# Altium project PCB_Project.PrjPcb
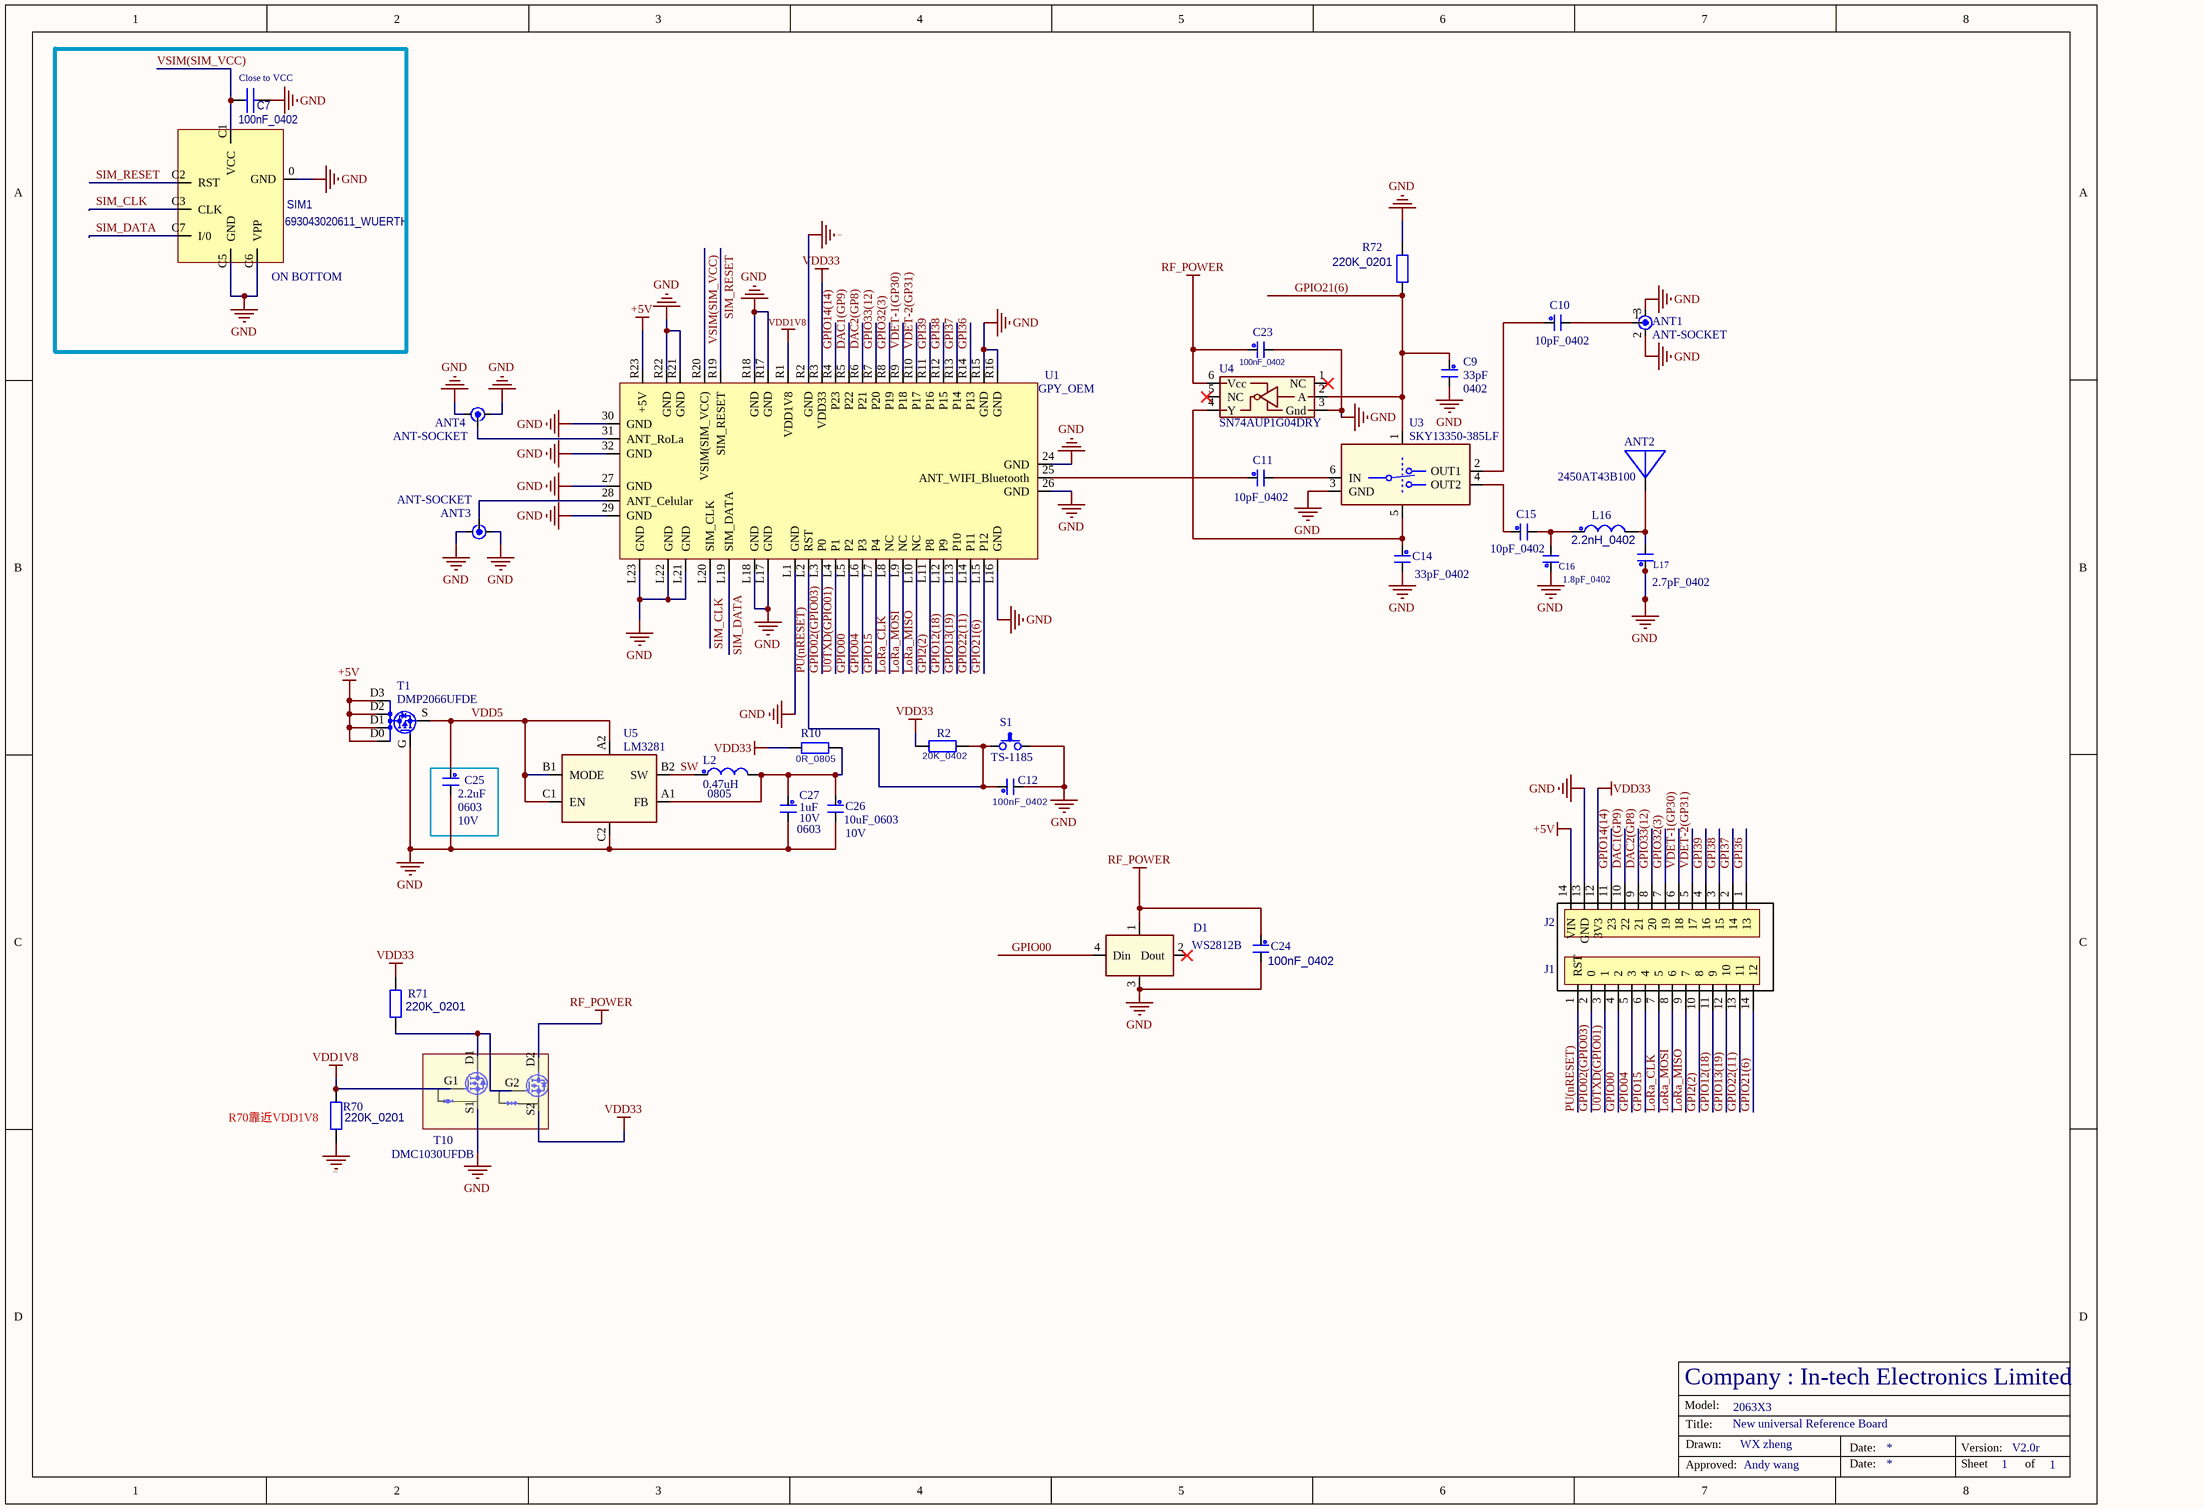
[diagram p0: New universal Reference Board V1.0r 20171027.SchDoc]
1 sheet, 36 parts. Net scope: global (net labels, ports and power ports of the same name join across sheets).
Board file: New universal Reference Board V1.0r 20171201.PcbDoc

## Sheet New universal Reference Board V1.0r 20171027.SchDoc: G01 Reference Board V1.0r
size A3; ApprovedBy: Andy wang; DrawnBy: WX zheng; Address1: 2063X3; Address2: New universal Reference Board; Address3: V2.0r; Address4: C; DocumentNumber: 1; SheetNumber: 1; SheetTotal: 1

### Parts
ANT1  ANT-SOCKET  [ANT-SOCKET]
ANT2  value 2450AT43B100  [ANT-2450AT43B100]  (hidden comment: ANT2450AT43B100)
ANT3  ANT-SOCKET  [ANT-SOCKET]
ANT4  ANT-SOCKET  [ANT-SOCKET]
C7  100nF_0402  [0402C]
C9  value 33pF  PCB DECAL: 0402  [0402C]  (hidden comment: 33pF_0402)
C10  10pF_0402  [0402C]
C11  10pF_0402  [0402C]
C12  100nF_0402  [0402C]
C14  33pF_0402  [0402C]
C15  10pF_0402  [0402CS]
C16  1.8pF_0402  [0402CS]
C23  100nF_0402  [0402C]
C24  100nF_0402  [0402C]
C25  value 2.2uF  Voltage Rating: 10V  FOOTPRINT: 0603  [0603C]  (hidden comment: 2.2UF_0603)
C26  10uF_0603  Voltage Rating: 10V  [0603C]
C27  value 1uF  Voltage Rating: 10V  footprint: 0603  [0603C]  (hidden comment: 1uF_0603)
D1  WS2812B  [WS2812B]
J1  CON14  [SYMHC101-14GA40]  (value not drawn)
J2  CON14  [SYMHC101-14GA40]  (value not drawn)
L2  value 0.47uH  PCB DECAL: 0805  [0805L]  (hidden comment: 0.47uH_0805)
L16  2.2nH_0402  [0402CS]
L17  2.7pF_0402  [0402CS]
R2  20K_0402  [0402R]
R10  0R_0805  [0805]
R70  220K_0201  [0201]
R71  220K_0201  [0201]
R72  220K_0201  [0201]
S1  TS-1185  [SW-TS-1185]
SIM1  693043020611_WUERTH  [SIM_FiPy]
T1  DMP2066UFDE  [U-DFN2020-6]
T10  DMC1030UFDB  [U-DFN2020-6 TYPE B]
U1  GPY_OEM  [NEW_OEM_FootPrint]
U3  value SKY13350-385LF  [MLPD-6]  (hidden comment: IC-SKY13350-385LF)
U4  value SN74AUP1G04DRY  [R-PUSON-N6(DRY)]  (hidden comment: IC-SN74AUP1G04DRY)
U5  value LM3281  [DSBGA6(YFQ)]  (hidden comment: IC-LM3281)

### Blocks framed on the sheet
ON BOTTOM: C7 SIM1

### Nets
+5V: J2.14(VIN) T1.D0 T1.D1 T1.D2 T1.D3 U1.R23(+5V)
GND: ANT1.2 ANT1.3 ANT3.2 ANT3.3 ANT4.2 ANT4.3 C7.2 C9.2 C12.2 C14.2 C16.1 C23.2 C24.2 C25.2 C26.2 C27.2 D1.3(Gnd) J2.13(GND) L17.1 R70.1 R72.1 S1.2 SIM1.0(GND) SIM1.C5(GND) SIM1.C6(VPP) T1.G T10.S1 U1.24(GND) U1.26(GND) U1.27(GND) U1.29(GND) U1.30(GND) U1.32(GND) U1.L1(GND) U1.L16(GND) U1.L17(GND) U1.L18(GND) U1.L21(GND) U1.L22(GND) U1.L23(GND) U1.R2(GND) U1.R15(GND) U1.R16(GND) U1.R17(GND) U1.R18(GND) U1.R21(GND) U1.R22(GND) U3.3(GND) U4.3(Gnd) U5.C2(Gnd)
RF_POWER: C23.1 C24.1 D1.1 T10.D2 U4.6(Vcc)
VDD1V8: R70.2 T10.G1 U1.R1(VDD1V8)
VDD33: J2.12(3V3) R2.1 R10.1 R71.2 T10.S2 U1.R3(VDD33)
DAC1(GP9): J2.10(22) U1.R5(P22)
DAC2(GP8): J2.9(21) U1.R6(P21)
GPI2(2): J1.10(8) U1.L11(P8)
GPI36: J2.1(13) U1.R14(P13)
GPI37: J2.2(14) U1.R13(P14)
GPI38: J2.3(15) U1.R12(P15)
GPI39: J2.4(16) U1.R11(P16)
GPIO00: D1.4(Din) J1.4(2) U1.L5(P2)
GPIO02(GPIO03): J1.2(0) U1.L3(P0)
GPIO04: J1.5(3) U1.L6(P3)
GPIO12(18): J1.11(9) U1.L12(P9)
GPIO13(19): J1.12(10) U1.L13(P10)
GPIO14(14): J2.11(23) U1.R4(P23)
GPIO15: J1.6(4) U1.L7(P4)
GPIO21(6): C9.1 J1.14(12) R72.2 U1.L15(P12) U3.1 U4.2(A)
GPIO22(11): J1.13(11) U1.L14(P11)
GPIO32(3): J2.7(19) U1.R8(P19)
GPIO33(12): J2.8(20) U1.R7(P20)
LoRa_CLK: J1.7(5) U1.L8(NC)
LoRa_MISO: J1.9(7) U1.L10(NC)
LoRa_MOSI: J1.8(6) U1.L9(NC)
PU(nRESET): C12.1 J1.1(RST) R2.2 S1.1 U1.L2(RST)
SIM_CLK: SIM1.C3(CLK) U1.L20(SIM_CLK)
SIM_DATA: SIM1.C7(I/0) U1.L19(SIM_DATA)
SIM_RESET: SIM1.C2(RST) U1.R19(SIM_RESET)
SW: L2.1 U5.B2(SW)
U0TXD(GPIO01): J1.3(1) U1.L4(P1)
VDD5: C25.1 T1.S U5.A2 U5.B1(MODE) U5.C1(EN)
VDET-1(GP30): J2.6(18) U1.R9(P18)
VDET-2(GP31): J2.5(17) U1.R10(P17)
VSIM(SIM_VCC): C7.1 SIM1.C1(VCC) U1.R20(VSIM(SIM_VCC))
NetANT1_1: ANT1.1 C10.2
NetANT2_1: ANT2.1 L16.2 L17.2
NetANT3_1: ANT3.1 U1.28(ANT_Celular)
NetANT4_1: ANT4.1 U1.31(ANT_RoLa)
NetC10_1: C10.1 U3.2(OUT1)
NetC11_1: C11.1 U1.25(ANT_WIFI_Bluetooth)
NetC11_2: C11.2 U3.6(IN)
NetC14_1: C14.1 U3.5 U4.4(Y)
NetC15_1: C15.1 U3.4(OUT2)
NetC15_2: C15.2 C16.2 L16.1
NetC26_1: C26.1 C27.1 L2.2 R10.2 U5.A1(FB)
NetR71_1: R71.1 T10.D1 T10.G2

Not connected (* = marked no-connect by the designer): D1 2(Dout)*; U4 1(NC)* 5(NC)*

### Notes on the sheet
- (near C7) Close to VCC
- (near R70) R70靠近VDD1V8
- Company : In-tech Electronics Limited
- Model:
- Title:
- Drawn:
- Date:
- Version:
- Approved:
- Sheet
- of

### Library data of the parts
ANT1 ANT3 ANT4 = ANT-SOCKET: Part Number: EKC-QB76725-00; Value: HJBRIGHT
ANT2 = ANT2450AT43B100: Part Number: EAT-6548454-00
C7 = CAP-2: SMD  Capacitor 0201
C9 = CC0402/33PF/J%: Part Number: ECH-004J330-21; Tolerance: +/-5%
C10 C11 = CC0402/10PF/D%: Part Number: ECH-004D100-21; Tolerance: +/-0.5pF; Voltage Rating: 50V; PCB DECAL: 0402
C12 C23 C24 = CC0402/100NF/K%16V: Part Number: ECH-012K104-39; Tolerance: +/-10 %; Voltage Rating: 16V
C14 = CC0402/33PF/J%: Part Number: ECH-004J330-21; Tolerance: +/-5%; PCB DECAL: 0402
C15 = CC0402/10PF/D%_S: Part Number: ECH-004D100-21; Tolerance: +/-0.5pF; Voltage Rating: 50V; PCB DECAL: 0402
C16 L17 = CC0402/0,5pF/+/-0.1pF_S: Part Number: ECH-004B059-37; PCB DECAL: 0402; Vender: Murata  GJM1555C1HR50BB01J D C0G/NP0
C25 C26 = CC0603/10UF/10V/K%: Part Number: ECH-181K106-04; Tolerance: +/-10 %
C27 = CC0603/1UF/K%/10V: Part Number: ECH-112K105-21; Tolerance: +/-10 %
D1 = DIO-WS2812B: Part Number: ESD-3M60AHK-11
L2 = IND0805/0.47uH/20%: Part Number: ELC-4Z0M474-11; Tolerance: +/-20%
L16 = IND0402/6.8nH/+/-0.1nH_S: Part Number: ELC-141B6N8-11; Tolerance: ±0.1nH; Vendor: Murata LQP15MN6N8B02D RF quality
R2 = RC0402/100K/F%: Part Number: ERH-10F4104-01; PCB DECAL: 0402; Tolerance: 1%
R10 = RC0402/100K/F%: Part Number: ERH-10F4104-01; PCB DECAL: 0402; Value: 0R; Tolerance: 1%
R70-R72 = RC0402/20K/F%: Part Number: ERH-10F2203-01; PCB DECAL: 0402
S1 = SW-TS-1185: Part Number: EKS-5M10685-11; VALUE2: PRG
SIM1 = SIM CARD
T1 = FET-P-DMP2066UFDE: Part number: EST-3451A6T-11
U1 = LOPYOEM_Mother_Board
U3 = IC-SKY13350-385LF: Part Number: ESC-1535A9P-00
U4 = IC-SN74AUP1G04DRY: Part Number: ESC-1186AUY-00
U5 = IC-LM3281: Part Number: ESC-1186AVV-00; PCB DECAL: SOT-23-5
